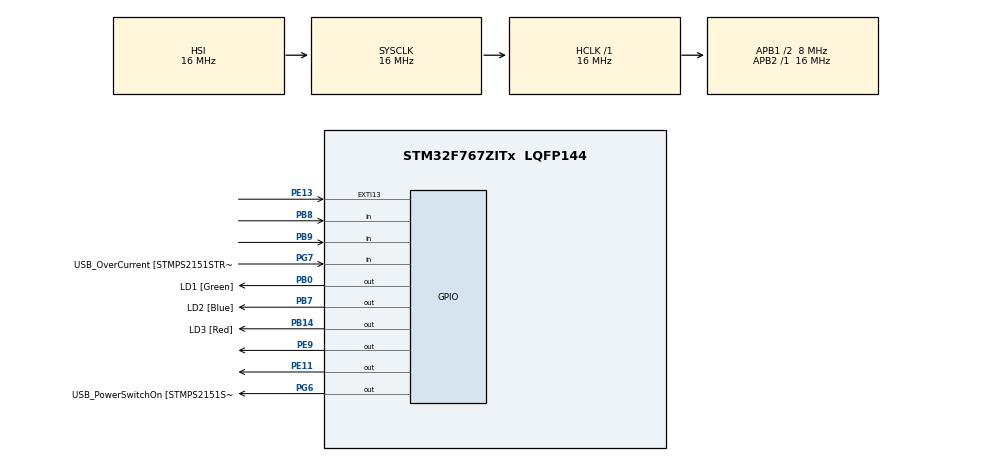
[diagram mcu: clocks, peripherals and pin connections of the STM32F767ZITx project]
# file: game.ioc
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Mcu.Family=STM32F7
Mcu.Name=STM32F767ZITx
Mcu.Package=LQFP144
NVIC.EXTI15_10_IRQn=true\:0\:0\:false\:false\:true\:true\:true\:true
NVIC.PriorityGroup=NVIC_PRIORITYGROUP_4
PA1.GPIO_Label=RMII_REF_CLK [LAN8742A-CZ-TR_REFCLK0]
PA1.Signal=ETH_REF_CLK
PA10.GPIO_Label=USB_ID
PA10.Signal=USB_OTG_FS_ID
PA11.GPIO_Label=USB_DM
PA11.Signal=USB_OTG_FS_DM
PA12.GPIO_Label=USB_DP
PA12.Signal=USB_OTG_FS_DP
PA13.GPIO_Label=TMS
PA13.Signal=SYS_JTMS-SWDIO
PA14.GPIO_Label=TCK
PA14.Signal=SYS_JTCK-SWCLK
PA2.GPIO_Label=RMII_MDIO [LAN8742A-CZ-TR_MDIO]
PA2.Signal=ETH_MDIO
PA7.GPIO_Label=RMII_CRS_DV [LAN8742A-CZ-TR_CRS_DV]
PA7.Signal=ETH_CRS_DV
PA8.GPIO_Label=USB_SOF [TP1]
PA8.Signal=USB_OTG_FS_SOF
PA9.GPIO_Label=USB_VBUS
PA9.Signal=USB_OTG_FS_VBUS
PB0.GPIO_Label=LD1 [Green]
PB0.Signal=GPIO_Output
PB13.GPIO_Label=RMII_TXD1 [LAN8742A-CZ-TR_TXD1]
PB13.Signal=ETH_TXD1
PB14.GPIO_Label=LD3 [Red]
PB14.Signal=GPIO_Output
PB3.GPIO_Label=SW0
PB3.Signal=SYS_JTDO-SWO
PB7.GPIO_Label=LD2 [Blue]
PB7.Signal=GPIO_Output
PB8.Signal=GPIO_Input
PB9.Signal=GPIO_Input
PC1.GPIO_Label=RMII_MDC [LAN8742A-CZ-TR_MDC]
PC1.Signal=ETH_MDC
PC14/OSC32_IN.Signal=RCC_OSC32_IN
PC15/OSC32_OUT.Signal=RCC_OSC32_OUT
PC4.GPIO_Label=RMII_RXD0 [LAN8742A-CZ-TR_RXD0]
PC4.Signal=ETH_RXD0
PC5.GPIO_Label=RMII_RXD1 [LAN8742A-CZ-TR_RXD1]
PC5.Signal=ETH_RXD1
PD8.GPIO_Label=STLK_RX [STM32F103CBT6_PA3]
PD8.Signal=USART3_TX
PD9.GPIO_Label=STLK_TX [STM32F103CBT6_PA2]
PD9.Signal=USART3_RX
PE11.Signal=GPIO_Output
PE13.Signal=GPXTI13
PE9.Signal=GPIO_Output
PG11.GPIO_Label=RMII_TX_EN [LAN8742A-CZ-TR_TXEN]
PG11.Signal=ETH_TX_EN
PG13.GPIO_Label=RMII_TXD0 [LAN8742A-CZ-TR_TXD0]
PG13.Signal=ETH_TXD0
PG6.GPIO_Label=USB_PowerSwitchOn [STMPS2151STR_EN]
PG6.Signal=GPIO_Output
PG7.GPIO_Label=USB_OverCurrent [STMPS2151STR_FAULT]
PG7.Signal=GPIO_Input
PH0/OSC_IN.GPIO_Label=MCO [STM32F103CBT6_PA8]
PH0/OSC_IN.Signal=RCC_OSC_IN
PH1/OSC_OUT.Signal=RCC_OSC_OUT
ProjectManager.HeapSize=0x200
ProjectManager.StackSize=0x400
ProjectManager.TargetToolchain=STM32CubeIDE
RCC.48MHZClocksFreq_Value=24000000
RCC.AHBFreq_Value=16000000
RCC.APB1CLKDivider=RCC_HCLK_DIV2
RCC.APB1Freq_Value=8000000
RCC.APB1TimFreq_Value=16000000
RCC.APB2Freq_Value=16000000
RCC.APB2TimFreq_Value=16000000
RCC.CortexFreq_Value=16000000
RCC.HCLKFreq_Value=16000000
RCC.HSE_VALUE=16000000
RCC.HSI_VALUE=16000000
RCC.LSE_VALUE=32768
RCC.PLLMUL=RCC_PLL_MUL9
RCC.PRESCALERUSB=RCC_USBCLKSOURCE_PLL_DIV1_5
RCC.SYSCLKFreq_VALUE=16000000
RCC.SYSCLKSourceVirtual=RCC_SYSCLKSOURCE_PLLCLK
RCC.USBFreq_Value=96000000
RCC.VCOOutputFreq_Value=192000000
board=NUCLEO-F767ZI

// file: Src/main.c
/* USER CODE BEGIN Header */
/**
  ******************************************************************************
  * @file           : main.c
  * @brief          : Main program body
  ******************************************************************************
  * @attention
  *
  * Copyright (c) 2025 STMicroelectronics.
  * All rights reserved.
  *
  * This software is licensed under terms that can be found in the LICENSE file
  * in the root directory of this software component.
  * If no LICENSE file comes with this software, it is provided AS-IS.
  *
  ******************************************************************************
  */
/* USER CODE END Header */
#include "main.h"

/* USER CODE BEGIN Includes */
#include <stdbool.h>

/* USER CODE END Includes */

/* USER CODE BEGIN PTD */
typedef enum
{
  PLAYER_NONE = 0U,
  PLAYER_ONE,
  PLAYER_TWO
} PlayerId;

typedef enum
{
  GAME_PHASE_ARMING = 0U,
  GAME_PHASE_WAIT_INPUT,
  GAME_PHASE_FINISHED
} GamePhase;

/* USER CODE END PTD */

void SystemClock_Config(void);
static void MX_GPIO_Init(void);
/* USER CODE BEGIN PFP */
static uint32_t generateRandomNumber(void);
static void showWinner(PlayerId winner);

/* USER CODE END PFP */

int main(void)
{

  /* MCU Configuration--------------------------------------------------------*/

  /* Reset of all peripherals, Initializes the Flash interface and the Systick. */
  HAL_Init();

  /* Configure the system clock */
  SystemClock_Config();

  /* Initialize all configured peripherals */
  MX_GPIO_Init();
  /* USER CODE BEGIN 2 */
  HAL_GPIO_WritePin(LD1_GPIO_Port, LD1_Pin, GPIO_PIN_RESET);
  HAL_GPIO_WritePin(LD2_GPIO_Port, LD2_Pin, GPIO_PIN_RESET);
  HAL_GPIO_WritePin(LD3_GPIO_Port, LD3_Pin, GPIO_PIN_RESET);

  const uint32_t minDelayMs = 0U;
  const uint32_t maxDelayMs = 20000U;
  uint32_t armDelayMs = minDelayMs + (generateRandomNumber() % (maxDelayMs - minDelayMs + 1U));
  uint32_t armStartTick = HAL_GetTick();
  GamePhase phase = GAME_PHASE_ARMING;
  PlayerId winner = PLAYER_NONE;
  bool prevP1Pressed = false;
  bool prevP2Pressed = false;
  /* USER CODE END 2 */

  /* Infinite loop */
  while (1)
  {

    /* USER CODE BEGIN 3 */
    uint32_t now = HAL_GetTick();
    bool p1Pressed = (HAL_GPIO_ReadPin(P1_GPIO_Port, P1_Pin) == GPIO_PIN_RESET);
    bool p2Pressed = (HAL_GPIO_ReadPin(P2_GPIO_Port, P2_Pin) == GPIO_PIN_RESET);
    bool p1Edge = p1Pressed && !prevP1Pressed;
    bool p2Edge = p2Pressed && !prevP2Pressed;

    if (phase == GAME_PHASE_ARMING)
    {
      if (p1Edge && p2Edge)
      {
        winner = PLAYER_NONE;
        phase = GAME_PHASE_FINISHED;
      }
      else if (p1Edge)
      {
        winner = PLAYER_TWO;
        phase = GAME_PHASE_FINISHED;
      }
      else if (p2Edge)
      {
        winner = PLAYER_ONE;
        phase = GAME_PHASE_FINISHED;
      }
      else if ((now - armStartTick) >= armDelayMs)
      {
        HAL_GPIO_WritePin(LD3_GPIO_Port, LD3_Pin, GPIO_PIN_SET);
        phase = GAME_PHASE_WAIT_INPUT;
      }
    }
    else if (phase == GAME_PHASE_WAIT_INPUT)
    {
      if (p1Edge && p2Edge)
      {
        winner = PLAYER_NONE;
        phase = GAME_PHASE_FINISHED;
      }
      else if (p1Edge)
      {
        winner = PLAYER_ONE;
        phase = GAME_PHASE_FINISHED;
      }
      else if (p2Edge)
      {
        winner = PLAYER_TWO;
        phase = GAME_PHASE_FINISHED;
      }
    }

    prevP1Pressed = p1Pressed;
    prevP2Pressed = p2Pressed;

    if (phase == GAME_PHASE_FINISHED)
    {
      break;
    }

    HAL_Delay(1);
  }

  HAL_GPIO_WritePin(LD3_GPIO_Port, LD3_Pin, GPIO_PIN_RESET);
  showWinner(winner);

  while (1)
  {
    /* Game finished: wait for hardware reset */
  }
  /* USER CODE END 3 */
}

void SystemClock_Config(void)
{
  RCC_OscInitTypeDef RCC_OscInitStruct = {0};
  RCC_ClkInitTypeDef RCC_ClkInitStruct = {0};

  /** Configure the main internal regulator output voltage
  */
  __HAL_RCC_PWR_CLK_ENABLE();
  __HAL_PWR_VOLTAGESCALING_CONFIG(PWR_REGULATOR_VOLTAGE_SCALE3);

  /** Initializes the RCC Oscillators according to the specified parameters
  * in the RCC_OscInitTypeDef structure.
  */
  RCC_OscInitStruct.OscillatorType = RCC_OSCILLATORTYPE_HSI;
  RCC_OscInitStruct.HSIState = RCC_HSI_ON;
  RCC_OscInitStruct.HSICalibrationValue = RCC_HSICALIBRATION_DEFAULT;
  RCC_OscInitStruct.PLL.PLLState = RCC_PLL_NONE;
  if (HAL_RCC_OscConfig(&RCC_OscInitStruct) != HAL_OK)
  {
    Error_Handler();
  }

  /** Initializes the CPU, AHB and APB buses clocks
  */
  RCC_ClkInitStruct.ClockType = RCC_CLOCKTYPE_HCLK|RCC_CLOCKTYPE_SYSCLK
                              |RCC_CLOCKTYPE_PCLK1|RCC_CLOCKTYPE_PCLK2;
  RCC_ClkInitStruct.SYSCLKSource = RCC_SYSCLKSOURCE_HSI;
  RCC_ClkInitStruct.AHBCLKDivider = RCC_SYSCLK_DIV1;
  RCC_ClkInitStruct.APB1CLKDivider = RCC_HCLK_DIV2;
  RCC_ClkInitStruct.APB2CLKDivider = RCC_HCLK_DIV1;

  if (HAL_RCC_ClockConfig(&RCC_ClkInitStruct, FLASH_LATENCY_0) != HAL_OK)
  {
    Error_Handler();
  }
}

static void MX_GPIO_Init(void)
{
  GPIO_InitTypeDef GPIO_InitStruct = {0};

  /* GPIO Ports Clock Enable */
  __HAL_RCC_GPIOB_CLK_ENABLE();

  /* Configure GPIO pin Output Level */
  HAL_GPIO_WritePin(GPIOB, LD1_Pin|LD2_Pin|LD3_Pin, GPIO_PIN_RESET);

  /* Configure GPIO pins : LD1_Pin LD2_Pin LD3_Pin */
  GPIO_InitStruct.Pin = LD1_Pin|LD2_Pin|LD3_Pin;
  GPIO_InitStruct.Mode = GPIO_MODE_OUTPUT_PP;
  GPIO_InitStruct.Pull = GPIO_NOPULL;
  GPIO_InitStruct.Speed = GPIO_SPEED_FREQ_LOW;
  HAL_GPIO_Init(GPIOB, &GPIO_InitStruct);

  /* Configure GPIO pins : P1_Pin P2_Pin */
  GPIO_InitStruct.Pin = P1_Pin|P2_Pin;
  GPIO_InitStruct.Mode = GPIO_MODE_INPUT;
  GPIO_InitStruct.Pull = GPIO_PULLUP;
  HAL_GPIO_Init(GPIOB, &GPIO_InitStruct);
}

/* USER CODE BEGIN 4 */
static void showWinner(PlayerId winner)
{
  GPIO_PinState p1State = GPIO_PIN_RESET;
  GPIO_PinState p2State = GPIO_PIN_RESET;

  if (winner == PLAYER_ONE)
  {
    p1State = GPIO_PIN_SET;
  }
  else if (winner == PLAYER_TWO)
  {
    p2State = GPIO_PIN_SET;
  }
  else if (winner == PLAYER_NONE)
  {
    p1State = GPIO_PIN_SET;
    p2State = GPIO_PIN_SET;
  }

  HAL_GPIO_WritePin(LD1_GPIO_Port, LD1_Pin, p1State);
  HAL_GPIO_WritePin(LD2_GPIO_Port, LD2_Pin, p2State);
}

static uint32_t generateRandomNumber(void)
{
  static uint32_t lcgState = 0U;

  if (lcgState == 0U)
  {
    uint32_t seed = HAL_GetTick() ^ SysTick->VAL ^ 0xA5A5A5A5U;

    if (seed == 0U)
    {
      seed = 0x13579BDFU;
    }

    lcgState = seed;
  }

  lcgState = (lcgState * 1664525U) + 1013904223U;
  return lcgState;
}
/* USER CODE END 4 */

void Error_Handler(void)
{
  __disable_irq();
  while (1)
  {
  }
}

#ifdef USE_FULL_ASSERT
/**
  * @brief  Reports the name of the source file and the source line number
  *         where the assert_param error has occurred.
  * @param  file: pointer to the source file name
  * @param  line: assert_param error line source number
  * @retval None
  */
void assert_failed(uint8_t *file, uint32_t line)
{
  /* USER CODE BEGIN 6 */
  (void)file;
  (void)line;
  /* USER CODE END 6 */
}
#endif /* USE_FULL_ASSERT */
